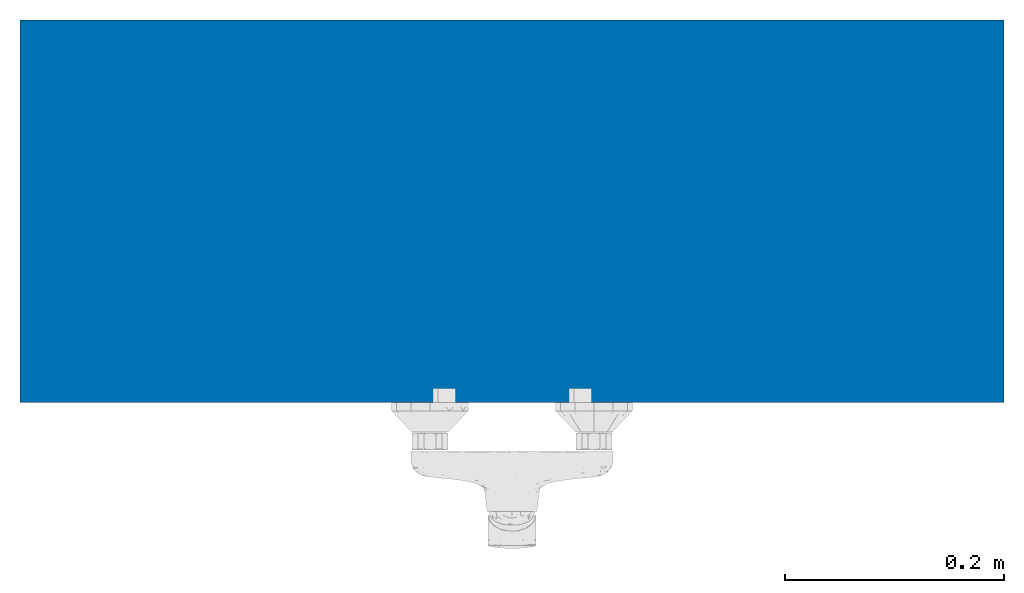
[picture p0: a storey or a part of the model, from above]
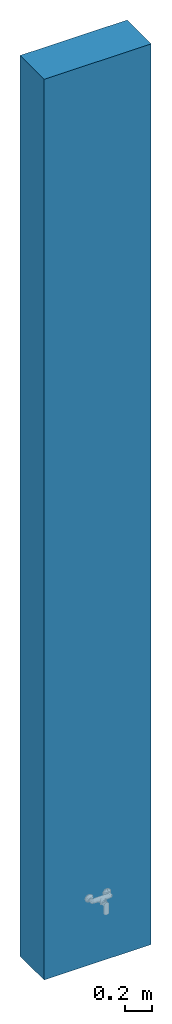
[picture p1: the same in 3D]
Properties of the parts of a building model (IFC2X3)

# File
Description: ViewDefinition [CoordinationView_V2.0]
File name: 0001
Time: 2024-08-23T13:13:20
Written by: The EXPRESS Data Manager Version 5.02.0100.07 : 28 Aug 2013
Made in: 21.1.90.15 - Exporter 21.1.90.15 - Alternate UI 21.1.90.15
Comment: STEP Physical File produced by: The EXPRESS Data Manager Version 5.02.0100.07 : 28 Aug 2013 * Module: EDMstepFileFactory/EDMstandAlone * Creation date: Fri Aug 23 13:13:20 2024 * Host: DCreative * Database: C:\Users\chatp\AppData\Local\Temp\60fd11f9-feae-4bd8-88c2-038f03fa110a\3e926e1b-ec10-4afa-aae1-2409e33570a7\ifc * Database version: 5507 * Database creation date: Fri Aug 23 13:13:16 2024 * Schema: IFC2X3 * Model: DataRepository.ifc * Model creation date: Fri Aug 23 13:13:16 2024 * Header model: DataRepository.ifc_HeaderModel * Header model creation date: Fri Aug 23 13:13:16 2024 * EDMuser: sdai-user * EDMgroup: sdai-group * License ID and type: 5605 : Permanent license. Expiry date: * EDMstepFileFactory options: 020000

# IfcProject, 0001
LongName: Project Name; Phase: Project Status

# IfcSite, Default
RefLatitude: 42, 21, 31, 181945; RefLongitude: -71, -3, -24, -263305; RefElevation: 0 mm
Pset_ProductRequirements - Category: Project Information

# IfcBuilding
Pset_BuildingCommon - NumberOfStoreys: 1
Pset_ProductRequirements - Category: Project Information

# IfcBuildingStorey: Level:8mm Head, Level 1
LongName: Level 1; Elevation: 0 mm
Pset_AirSideSystemInformation - Name: Level 1
Pset_ProductRequirements - Name: Level 1; Category: Levels

# IfcBuildingElementProxy: FFAS1M12-709500BF0_REVIT:Loven Exposed Shower Mixer W/O Shower, FFAS1M12-709500BF0_REVIT:Loven Exposed Shower Mixer W/O Shower:348728
In: Level 1
Type - Material: American Standard - Chrome, American Standard - Zinc Die Cast-Plastic
Type - Pset_BuildingElementProxyCommon - Reference: Loven Exposed Shower Mixer W/O Shower
Type - Pset_ManufacturerTypeInformation - Manufacturer: American Standard
Type - Pset_ProductRequirements - Category: Specialty Equipment
Type - Pset_QuantityTakeOff - Reference: Loven Exposed Shower Mixer W/O Shower
Type - Pset_ProvisionForVoid - Width: 132 mm; Height: 131 mm
Material: American Standard - Chrome
Pset_BuildingElementProxyCommon - sets with these values: 2

# IfcDistributionPort (2)
Description: Flow; FlowDirection: SOURCE

# IfcWallStandardCase: Basic Wall:Exterior - Brick on Mtl. Stud, Basic Wall:Exterior - Brick on Mtl. Stud:347048
In: Level 1
Type - PredefinedType: STANDARD
Type - Pset_ElementShading - Roughness: 914.4 mm
Type - Pset_ProductRequirements - Category: Walls
Type - Pset_QuantityTakeOff - Reference: Exterior - Brick on Mtl. Stud
Type - Pset_ReinforcementBarPitchOfWall - Reference: Exterior - Brick on Mtl. Stud
Type - Pset_WallCommon - Reference: Exterior - Brick on Mtl. Stud; IsExternal: no
Pset_QuantityTakeOff - sets with these values: 2
Pset_WallCommon - IsExternal: yes; ExtendToStructure: no; LoadBearing: no
